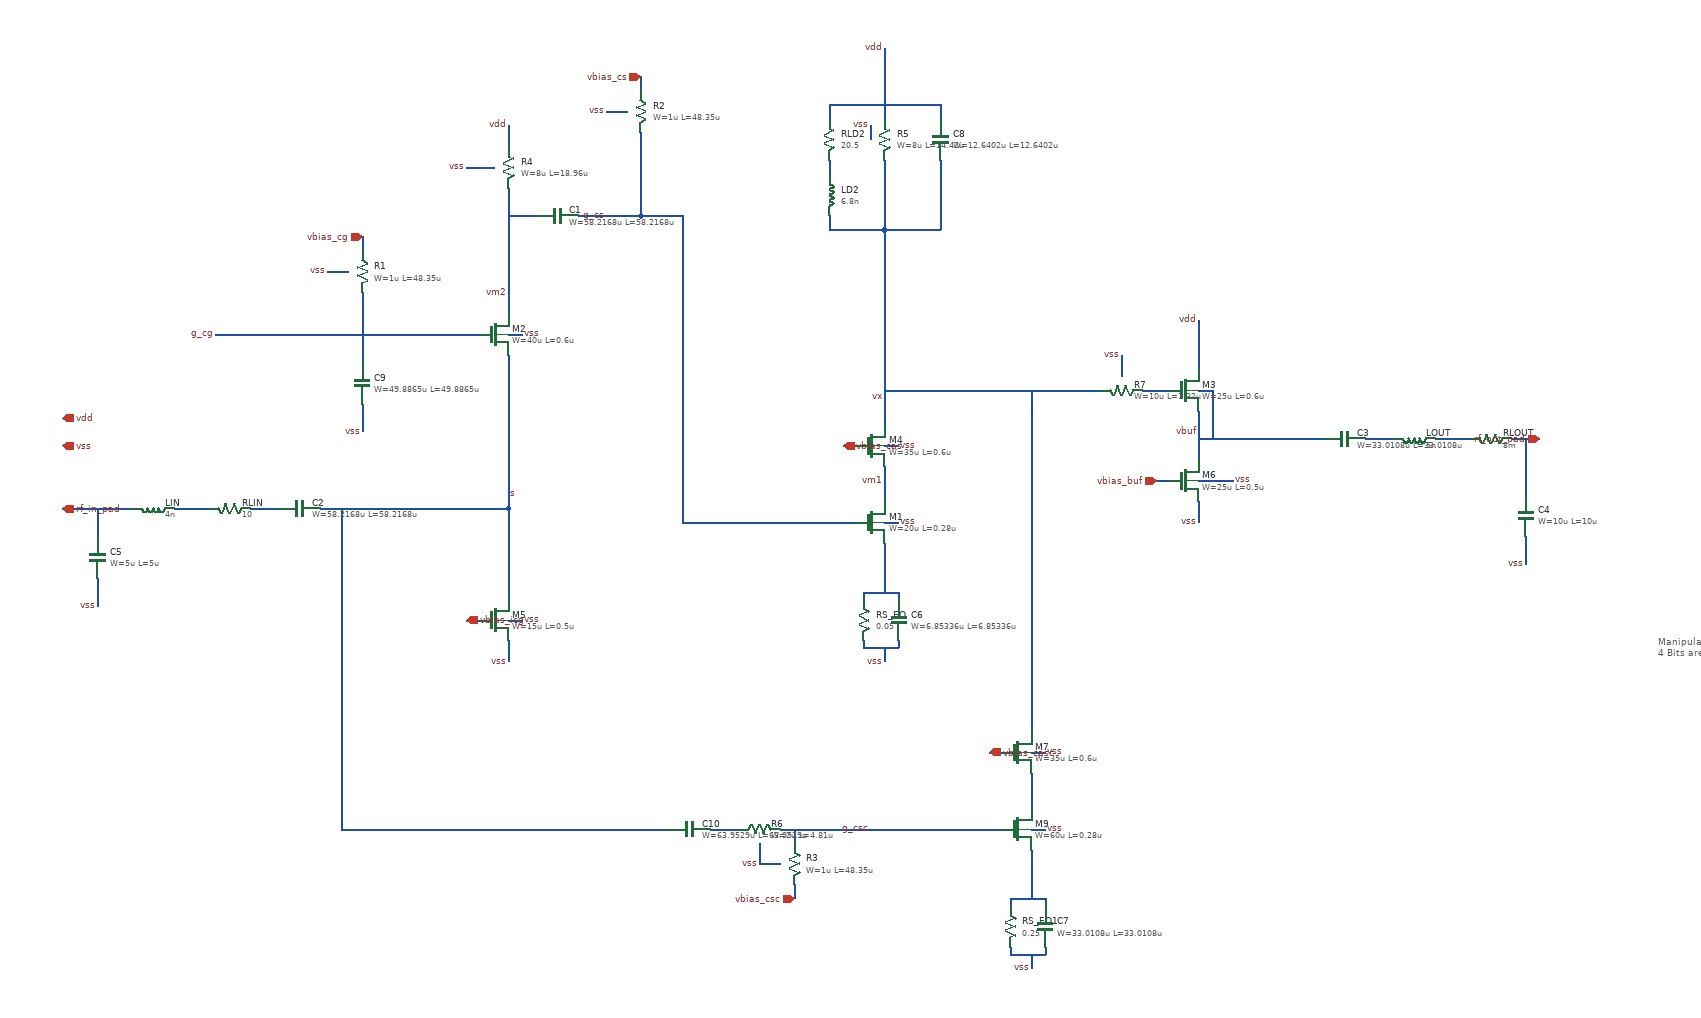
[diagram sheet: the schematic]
v {xschem version=3.4.8RC file_version=1.3}
G {}
K {}
V {}
S {}
F {}
E {}
T {Manipulate m of XC4 from 1 to 16
4 Bits are needed} 2410 -400 2 0 0.4 0.4 {}
N 760 -830 780 -830 {
lab=vss}
N 760 -1040 760 -960 {
lab=vm2}
N 760 -1130 760 -1100 {
lab=vdd}
N 490 -580 510 -580 {
lab=s}
N 160 -580 190 -580 {
lab=rf_in_pad}
N 760 -1000 800 -1000 {
lab=vm2}
N 860 -1000 900 -1000 {
lab=g_cs}
N 760 -620 760 -610 {
lab=s}
N 760 -610 760 -580 {
lab=s}
N 700 -830 720 -830 {
lab=g_cg}
N 550 -970 550 -950 {
lab=vbias_cg}
N 550 -730 550 -690 {
lab=vss}
N 1300 -560 1320 -560 {
lab=vss}
N 1300 -530 1300 -520 {
lab=#net1}
N 1240 -560 1260 -560 {
lab=g_cs}
N 950 -1200 950 -1180 {
lab=vbias_cs}
N 950 -1120 950 -1090 {
lab=g_cs}
N 1300 -520 1300 -460 {
lab=#net1}
N 1300 -1180 1300 -1140 {
lab=vdd}
N 1750 -850 1750 -780 {
lab=vdd}
N 1750 -720 1750 -650 {
lab=vbuf}
N 1750 -590 1750 -560 {
lab=vss}
N 1750 -750 1770 -750 {
lab=vbuf}
N 1890 -680 1930 -680 {
lab=vbuf}
N 1990 -680 2030 -680 {
lab=vbuf}
N 2090 -680 2140 -680 {
lab=vbuf}
N 2200 -680 2240 -680 {
lab=rf_out_pad}
N 2220 -680 2220 -600 {
lab=rf_out_pad
spice_ignore=short}
N 2220 -540 2220 -500 {
lab=vss
}
N 170 -580 170 -540 {
lab=rf_in_pad}
N 170 -480 170 -440 {
lab=vss}
N 190 -580 220 -580 {
lab=rf_in_pad}
N 280 -580 330 -580 {
lab=#net2}
N 390 -580 430 -580 {
lab=#net3}
N 1300 -670 1320 -670 {
lab=vss}
N 1300 -640 1300 -630 {
lab=vm1}
N 1240 -670 1260 -670 {
lab=vbias_cas}
N 1300 -1080 1300 -1000 {
lab=vx}
N 1300 -630 1300 -590 {
lab=vm1}
N 1770 -750 1770 -700 {
lab=vbuf}
N 760 -420 780 -420 {
lab=vss}
N 760 -390 760 -380 {
lab=vss}
N 700 -420 720 -420 {
lab=vbias_icg}
N 760 -380 760 -360 {
lab=vss}
N 1750 -620 1800 -620 {
lab=vss}
N 1320 -460 1320 -450 {
lab=#net1}
N 1270 -460 1320 -460 {
lab=#net1}
N 1320 -390 1320 -380 {
lab=vss}
N 1270 -380 1320 -380 {
lab=vss}
N 1270 -460 1270 -450 {
lab=#net1}
N 1270 -390 1270 -380 {
lab=vss}
N 1300 -380 1300 -360 {
lab=vss}
N 1670 -750 1710 -750 {
lab=#net4}
N 1300 -750 1370 -750 {
lab=vx}
N 1510 -120 1530 -120 {
lab=vss
spice_ignore=true}
N 1510 -90 1510 -80 {
lab=#net7
spice_ignore=true}
N 1450 -120 1470 -120 {
lab=g_csc
spice_ignore=true}
N 1170 -40 1170 -20 {
lab=vbias_csc
spice_ignore=true}
N 1510 -80 1510 -20 {
lab=#net7
spice_ignore=true}
N 1510 -230 1530 -230 {
lab=vss
spice_ignore=true}
N 1510 -200 1510 -190 {
lab=#net8
spice_ignore=true}
N 1450 -230 1470 -230 {
lab=vbias_casc
spice_ignore=true}
N 1510 -720 1510 -640 {
lab=vx}
N 1510 -190 1510 -150 {
lab=#net8
spice_ignore=true}
N 1530 -20 1530 -10 {
lab=#net7
spice_ignore=true}
N 1480 -20 1530 -20 {
lab=#net7
spice_ignore=true}
N 1530 50 1530 60 {
lab=vss
spice_ignore=true}
N 1480 60 1530 60 {
lab=vss
spice_ignore=true}
N 1480 -20 1480 -10 {
lab=#net7
spice_ignore=true}
N 1480 50 1480 60 {
lab=vss
spice_ignore=true}
N 1510 60 1510 80 {
lab=vss
spice_ignore=true}
N 1050 -120 1090 -120 {
lab=#net9
spice_ignore=true}
N 760 -900 760 -890 {
lab=vm2}
N 760 -890 760 -860 {lab=vm2}
N 1220 -1160 1220 -1140 {lab=vdd}
N 1220 -1160 1300 -1160 {lab=vdd}
N 1220 -1080 1220 -1060 {lab=#net5}
N 1380 -1080 1380 -1070 {lab=vx}
N 1300 -980 1380 -980 {lab=vx}
N 1380 -1160 1380 -1140 {lab=vdd}
N 1300 -1160 1380 -1160 {lab=vdd}
N 1380 -1070 1380 -1060 {lab=vx}
N 760 -960 760 -900 {lab=vm2}
N 1220 -1000 1220 -980 {lab=vx}
N 1220 -980 1300 -980 {lab=vx}
N 1380 -1060 1380 -980 {lab=vx}
N 1150 -120 1180 -120 {lab=g_csc
spice_ignore=true}
N 900 -1150 930 -1150 {lab=vss}
N 1120 -70 1150 -70 {lab=vss
spice_ignore=true}
N 500 -920 530 -920 {lab=vss}
N 700 -1070 740 -1070 {lab=vss}
N 1280 -1130 1280 -1110 {lab=vss}
N 1300 -1240 1300 -1180 {lab=vdd}
N 1120 -100 1120 -70 {lab=vss
spice_ignore=true}
N 1640 -800 1640 -770 {lab=vss}
N 550 -830 550 -790 {lab=g_cg}
N 930 -120 990 -120 {lab=s
spice_ignore=true}
N 760 -580 760 -450 {lab=s}
N 510 -580 760 -580 {lab=s}
N 1180 -120 1310 -120 {lab=g_csc
spice_ignore=true}
N 1170 -120 1170 -100 {lab=g_csc
spice_ignore=true}
N 1310 -120 1450 -120 {lab=g_csc
spice_ignore=true}
N 760 -800 760 -620 {lab=s}
N 340 -830 700 -830 {lab=g_cg}
N 550 -890 550 -830 {lab=g_cg}
N 900 -1000 950 -1000 {lab=g_cs}
N 950 -1090 950 -1000 {lab=g_cs}
N 950 -1000 1010 -1000 {lab=g_cs}
N 1010 -1000 1010 -560 {lab=g_cs}
N 1010 -560 1240 -560 {lab=g_cs}
N 1300 -980 1300 -760 {lab=vx}
N 1300 -760 1300 -700 {lab=vx}
N 520 -120 930 -120 {lab=s
spice_ignore=true}
N 520 -290 520 -260 {lab=s
spice_ignore=true}
N 1510 -750 1510 -720 {lab=vx}
N 1300 -1000 1300 -980 {lab=vx}
N 1370 -750 1610 -750 {lab=vx}
N 1750 -680 1890 -680 {lab=vbuf}
N 1510 -640 1510 -400 {lab=vx}
N 520 -580 520 -290 {lab=s}
N 1690 -620 1710 -620 {lab=vbias_buf}
N 120 -580 160 -580 {lab=rf_in_pad}
N 1510 -400 1510 -260 {lab=vx
}
N 520 -260 520 -120 {lab=s
spice_ignore=true}
N 1770 -700 1770 -680 {lab=vbuf}
C {lab_pin.sym} 760 -1130 0 0 {name=p11 sig_type=std_logic lab=vdd
}
C {lab_wire.sym} 900 -1000 0 0 {name=p14 sig_type=std_logic lab=g_cs}
C {lab_pin.sym} 760 -600 2 0 {name=p1 sig_type=std_logic lab=s}
C {symbols/nfet_06v0.sym} 740 -830 0 0 {name=M2
L=0.6u
W=40u
nf=10
m=14
ad="'int((nf+1)/2) * W/nf * 0.18u'"
pd="'2*int((nf+1)/2) * (W/nf + 0.18u)'"
as="'int((nf+2)/2) * W/nf * 0.18u'"
ps="'2*int((nf+2)/2) * (W/nf + 0.18u)'"
nrd="'0.18u / W'" nrs="'0.18u / W'"
sa=0 sb=0 sd=0
model=nfet_06v0
spiceprefix=X
}
C {lab_pin.sym} 340 -830 0 0 {name=p4 sig_type=std_logic lab=g_cg}
C {lab_pin.sym} 1300 -1240 0 0 {name=p39 sig_type=std_logic lab=vdd
}
C {symbols/nfet_06v0.sym} 1730 -750 0 0 {name=M3
L=0.6u
W=25u
nf=10
m=15
ad="'int((nf+1)/2) * W/nf * 0.18u'"
pd="'2*int((nf+1)/2) * (W/nf + 0.18u)'"
as="'int((nf+2)/2) * W/nf * 0.18u'"
ps="'2*int((nf+2)/2) * (W/nf + 0.18u)'"
nrd="'0.18u / W'" nrs="'0.18u / W'"
sa=0 sb=0 sd=0
model=nfet_06v0
spiceprefix=X
}
C {lab_pin.sym} 1750 -850 0 0 {name=p40 sig_type=std_logic lab=vdd
}
C {lab_pin.sym} 1750 -690 0 0 {name=p43 sig_type=std_logic lab=vbuf}
C {ind.sym} 2060 -680 1 0 {name=LOUT
m=1
value=5n
footprint=1206
device=inductor
spice_ignore=short}
C {res.sym} 2170 -680 1 0 {name=RLOUT
value=8m
footprint=1206
device=resistor
m=1
}
C {lab_pin.sym} 170 -440 3 0 {name=p46 sig_type=std_logic lab=vss}
C {ind.sym} 250 -580 1 0 {name=LIN
m=1
value=4n
footprint=1206
device=inductor
}
C {res.sym} 360 -580 1 0 {name=RLIN
value=10
footprint=1206
device=resistor
m=1
}
C {symbols/nfet_06v0.sym} 1280 -670 0 0 {name=M4
L=0.6u
W=35u
nf=10
m=4
ad="'int((nf+1)/2) * W/nf * 0.18u'"
pd="'2*int((nf+1)/2) * (W/nf + 0.18u)'"
as="'int((nf+2)/2) * W/nf * 0.18u'"
ps="'2*int((nf+2)/2) * (W/nf + 0.18u)'"
nrd="'0.18u / W'" nrs="'0.18u / W'"
sa=0 sb=0 sd=0
model=nfet_06v0
spiceprefix=X
}
C {symbols/nfet_03v3.sym} 740 -420 0 0 {name=M5
L=0.5u
W=15u
nf=10
m=1
ad="'int((nf+1)/2) * W/nf * 0.18u'"
pd="'2*int((nf+1)/2) * (W/nf + 0.18u)'"
as="'int((nf+2)/2) * W/nf * 0.18u'"
ps="'2*int((nf+2)/2) * (W/nf + 0.18u)'"
nrd="'0.18u / W'" nrs="'0.18u / W'"
sa=0 sb=0 sd=0
model=nfet_03v3
spiceprefix=X
}
C {symbols/nfet_03v3.sym} 1730 -620 0 0 {name=M6
L=0.5u
W=25u
nf=10
m=5
ad="'int((nf+1)/2) * W/nf * 0.18u'"
pd="'2*int((nf+1)/2) * (W/nf + 0.18u)'"
as="'int((nf+2)/2) * W/nf * 0.18u'"
ps="'2*int((nf+2)/2) * (W/nf + 0.18u)'"
nrd="'0.18u / W'" nrs="'0.18u / W'"
sa=0 sb=0 sd=0
model=nfet_03v3
spiceprefix=X
}
C {res.sym} 1270 -420 0 0 {name=RS_EQ
value=0.05
footprint=1206
device=resistor
m=1
}
C {symbols/nfet_03v3.sym} 1280 -560 0 0 {name=M1
L=0.28u
W=20u
nf=10
m=10
ad="'int((nf+1)/2) * W/nf * 0.18u'"
pd="'2*int((nf+1)/2) * (W/nf + 0.18u)'"
as="'int((nf+2)/2) * W/nf * 0.18u'"
ps="'2*int((nf+2)/2) * (W/nf + 0.18u)'"
nrd="'0.18u / W'" nrs="'0.18u / W'"
sa=0 sb=0 sd=0
model=nfet_03v3
spiceprefix=X
}
C {symbols/nfet_06v0.sym} 1490 -230 0 0 {name=M7
L=0.6u
W=35u
nf=10
m=2
ad="'int((nf+1)/2) * W/nf * 0.18u'"
pd="'2*int((nf+1)/2) * (W/nf + 0.18u)'"
as="'int((nf+2)/2) * W/nf * 0.18u'"
ps="'2*int((nf+2)/2) * (W/nf + 0.18u)'"
nrd="'0.18u / W'" nrs="'0.18u / W'"
sa=0 sb=0 sd=0
model=nfet_06v0
spiceprefix=X
spice_ignore=true}
C {res.sym} 1480 20 0 0 {name=RS_EQ1
value=0.25
footprint=1206
device=resistor
m=1
spice_ignore=true}
C {symbols/nfet_03v3.sym} 1490 -120 0 0 {name=M9
L=0.28u
W=60u
nf=4
m=4
ad="'int((nf+1)/2) * W/nf * 0.18u'"
pd="'2*int((nf+1)/2) * (W/nf + 0.18u)'"
as="'int((nf+2)/2) * W/nf * 0.18u'"
ps="'2*int((nf+2)/2) * (W/nf + 0.18u)'"
nrd="'0.18u / W'" nrs="'0.18u / W'"
sa=0 sb=0 sd=0
model=nfet_03v3
spiceprefix=X
spice_ignore=true}
C {lab_pin.sym} 1300 -740 0 0 {name=p36 sig_type=std_logic lab=vx}
C {lab_wire.sym} 1280 -120 0 0 {name=p68 sig_type=std_logic lab=g_csc
spice_ignore=true}
C {lab_pin.sym} 760 -888.75 0 0 {name=p71 sig_type=std_logic lab=vm2}
C {lab_pin.sym} 1300 -618.75 0 0 {name=p72 sig_type=std_logic lab=vm1}
C {ind.sym} 1220 -1030 0 0 {name=LD2
m=1
value=6.8n
footprint=1206
device=inductor
}
C {res.sym} 1220 -1110 0 0 {name=RLD2
value=20.5
footprint=1206
device=resistor
m=1
}
C {symbols/ppolyf_u_1k.sym} 950 -1150 2 1 {name=R2
W=1u
L=48.35u
model=ppolyf_u_1k
spiceprefix=X
m=1}
C {symbols/ppolyf_u_1k.sym} 1170 -70 0 0 {name=R3
W=1u
L=48.35u
model=ppolyf_u_1k
spiceprefix=X
m=1
spice_ignore=true}
C {symbols/ppolyf_u_1k.sym} 550 -920 2 1 {name=R1
W=1u
L=48.35u
model=ppolyf_u_1k
spiceprefix=X
m=1}
C {symbols/ppolyf_u.sym} 760 -1070 0 0 {name=R4
W=8u
L=18.96u
model=ppolyf_u
spiceprefix=X
m=1}
C {symbols/ppolyf_u.sym} 1300 -1110 0 0 {name=R5
W=8u
L=14.42u
model=ppolyf_u
spiceprefix=X
m=1}
C {symbols/npolyf_s.sym} 1120 -120 3 0 {name=R6
W=2u
L=4.81u
model=npolyf_s
spiceprefix=X
m=1
spice_ignore=true}
C {symbols/npolyf_s.sym} 1640 -750 1 0 {name=R7
W=10u
L=1.32u
model=npolyf_s
spiceprefix=X
m=1}
C {symbols/cap_mim_2f0fF.sym} 830 -1000 1 0 {name=C1
W=58.2168u
L=58.2168u
model=cap_mim_2f0_m4m5_noshield
spiceprefix=X
m=1}
C {symbols/cap_mim_2f0fF.sym} 460 -580 1 0 {name=C2
W=58.2168u
L=58.2168u
model=cap_mim_2f0_m4m5_noshield
spiceprefix=X
m=1
}
C {symbols/cap_mim_2f0fF.sym} 1960 -680 1 0 {name=C3
W=33.0108u
L=33.0108u
model=cap_mim_2f0_m4m5_noshield
spiceprefix=X
m=4
spice_ignore=short}
C {symbols/cap_mim_2f0fF.sym} 2220 -570 0 0 {name=C4
W=10u
L=10u
model=cap_mim_2f0_m4m5_noshield
spiceprefix=X
m=1
}
C {symbols/cap_mim_2f0fF.sym} 170 -510 0 0 {name=C5
W=5u
L=5u
model=cap_mim_2f0_m4m5_noshield
spiceprefix=X
m=1
}
C {symbols/cap_mim_2f0fF.sym} 1320 -420 0 0 {name=C6
W=6.85336u
L=6.85336u
model=cap_mim_2f0_m4m5_noshield
spiceprefix=X
m=1}
C {symbols/cap_mim_2f0fF.sym} 1530 20 0 0 {name=C7
W=33.0108u
L=33.0108u
model=cap_mim_2f0_m4m5_noshield
spiceprefix=X
m=1
spice_ignore=true}
C {symbols/cap_mim_2f0fF.sym} 1380 -1110 0 0 {name=C8
W=12.6402u
L=12.6402u
model=cap_mim_2f0_m4m5_noshield
spiceprefix=X
m=1}
C {symbols/cap_mim_2f0fF.sym} 550 -760 2 1 {name=C9
W=49.8865u
L=49.8865u
model=cap_mim_2f0_m4m5_noshield
spiceprefix=X
m=4}
C {symbols/cap_mim_2f0fF.sym} 1020 -120 3 0 {name=C10
W=63.9529u
L=63.9529u
model=cap_mim_2f0_m4m5_noshield
spiceprefix=X
m=1
spice_ignore=true}
C {iopin.sym} 120 -580 0 1 {name=p56 lab=rf_in_pad}
C {iopin.sym} 550 -970 3 0 {name=p57 lab=vbias_cg}
C {iopin.sym} 2240 -680 0 0 {name=p58 lab=rf_out_pad}
C {iopin.sym} 950 -1200 3 0 {name=p59 lab=vbias_cs
}
C {iopin.sym} 120 -710 0 1 {name=p60 lab=vdd}
C {iopin.sym} 1240 -670 0 1 {name=p61 lab=vbias_cas}
C {iopin.sym} 120 -670 0 1 {name=p62 lab=vss}
C {iopin.sym} 1450 -230 0 1 {name=p63 lab=vbias_casc
spice_ignore=true}
C {iopin.sym} 1690 -620 2 0 {name=p64 lab=vbias_buf}
C {iopin.sym} 700 -420 0 1 {name=p65 lab=vbias_icg}
C {iopin.sym} 1170 -20 1 0 {name=p79 lab=vbias_csc
spice_ignore=true}
C {lab_pin.sym} 760 -360 3 0 {name=p5 sig_type=std_logic lab=vss}
C {lab_pin.sym} 1510 80 3 0 {name=p6 sig_type=std_logic lab=vss
spice_ignore=true}
C {lab_pin.sym} 1300 -360 3 0 {name=p7 sig_type=std_logic lab=vss}
C {lab_pin.sym} 1750 -560 3 0 {name=p8 sig_type=std_logic lab=vss}
C {lab_pin.sym} 2220 -500 3 0 {name=p9 sig_type=std_logic lab=vss
}
C {lab_pin.sym} 550 -690 3 0 {name=p10 sig_type=std_logic lab=vss}
C {lab_pin.sym} 780 -420 2 0 {name=p2 sig_type=std_logic lab=vss}
C {lab_pin.sym} 780 -830 2 0 {name=p12 sig_type=std_logic lab=vss}
C {lab_pin.sym} 700 -1070 0 0 {name=p16 sig_type=std_logic lab=vss}
C {lab_pin.sym} 1530 -120 2 0 {name=p26 sig_type=std_logic lab=vss
spice_ignore=true}
C {lab_pin.sym} 1530 -230 2 0 {name=p27 sig_type=std_logic lab=vss
spice_ignore=true}
C {lab_pin.sym} 500 -920 2 1 {name=p3 sig_type=std_logic lab=vss}
C {lab_pin.sym} 900 -1150 2 1 {name=p31 sig_type=std_logic lab=vss}
C {lab_pin.sym} 1120 -70 3 0 {name=p33 sig_type=std_logic lab=vss
spice_ignore=true}
C {lab_pin.sym} 1280 -1130 1 0 {name=p34 sig_type=std_logic lab=vss}
C {lab_pin.sym} 1640 -800 1 0 {name=p35 sig_type=std_logic lab=vss}
C {lab_pin.sym} 1320 -670 2 0 {name=p41 sig_type=std_logic lab=vss}
C {lab_pin.sym} 1320 -560 2 0 {name=p42 sig_type=std_logic lab=vss}
C {lab_pin.sym} 1800 -620 2 0 {name=p48 sig_type=std_logic lab=vss}
